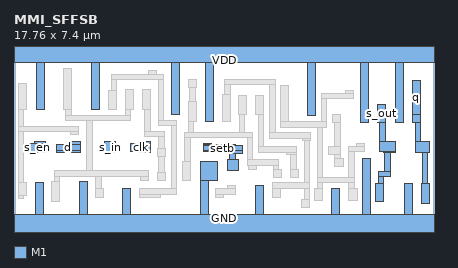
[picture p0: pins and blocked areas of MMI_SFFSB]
MACRO MMI_SFFSB
	CLASS CORE ;
	FOREIGN MMI_SFFSB 0 0 ;
	SIZE 17.76 BY 7.4 ;
	SYMMETRY X Y ;
	SITE CORE1 ;
	PIN d
		DIRECTION input ;
		USE SIGNAL ;
		PORT
			LAYER M1 ;
			RECT 1.79 3.435 2.13 3.465 ;
			LAYER M1 ;
			RECT 2.365 3.435 2.815 3.555 ;
			LAYER M1 ;
			RECT 1.79 3.205 2.815 3.435 ;
			LAYER M1 ;
			RECT 1.79 3.125 2.13 3.205 ;
			LAYER M1 ;
			RECT 2.365 3.105 2.815 3.205 ;
		END
		AntennaGateArea 0.4968 ;
	END d
	PIN GND
		DIRECTION inout ;
		USE GROUND ;
		PORT
			LAYER M1 ;
			RECT 7.905 1.905 8.6 2.745 ;
			LAYER M1 ;
			RECT 0.9 0.5 1.24 1.82 ;
			LAYER M1 ;
			RECT 2.75 0.5 3.09 1.87 ;
			LAYER M1 ;
			RECT 4.6 0.5 4.94 1.57 ;
			LAYER M1 ;
			RECT 7.905 0.5 8.245 1.905 ;
			LAYER M1 ;
			RECT 10.215 0.5 10.555 1.705 ;
			LAYER M1 ;
			RECT 13.445 0.5 13.785 1.6 ;
			LAYER M1 ;
			RECT 14.735 0.5 15.075 2.855 ;
			LAYER M1 ;
			RECT 16.495 0.5 16.835 1.8 ;
			LAYER M1 ;
			RECT 0 -0.5 17.76 0.5 ;
		END
	END GND
	PIN q
		DIRECTION output ;
		USE SIGNAL ;
		PORT
			LAYER M1 ;
			RECT 16.84 4.73 17.18 6.15 ;
			LAYER M1 ;
			RECT 16.84 4.39 17.19 4.73 ;
			LAYER M1 ;
			RECT 16.96 3.555 17.19 4.39 ;
			LAYER M1 ;
			RECT 16.96 3.11 17.56 3.555 ;
			LAYER M1 ;
			RECT 17.265 1.8 17.495 3.11 ;
			LAYER M1 ;
			RECT 17.215 0.96 17.555 1.8 ;
		END
		AntennaDiffArea 1.3248 ;
	END q
	PIN s_in
		DIRECTION input ;
		USE SIGNAL ;
		PORT
			LAYER M1 ;
			RECT 3.845 3.105 4.295 3.555 ;
		END
		AntennaGateArea 0.2484 ;
	END s_in
	PIN s_en
		DIRECTION input ;
		USE SIGNAL ;
		PORT
			LAYER M1 ;
			RECT 0.885 3.5 1.335 3.555 ;
			LAYER M1 ;
			RECT 0.66 3.16 1.335 3.5 ;
			LAYER M1 ;
			RECT 0.885 3.105 1.335 3.16 ;
		END
		AntennaGateArea 1.0404 ;
	END s_en
	PIN VDD
		DIRECTION inout ;
		USE POWER ;
		PORT
			LAYER M1 ;
			RECT 0 6.9 17.76 7.9 ;
			LAYER M1 ;
			RECT 0.94 4.91 1.28 6.9 ;
			LAYER M1 ;
			RECT 3.28 4.91 3.62 6.9 ;
			LAYER M1 ;
			RECT 6.65 4.705 6.99 6.9 ;
			LAYER M1 ;
			RECT 8.09 4.43 8.43 6.9 ;
			LAYER M1 ;
			RECT 12.42 4.66 12.76 6.9 ;
			LAYER M1 ;
			RECT 14.64 4.39 14.98 6.9 ;
			LAYER M1 ;
			RECT 16.12 4.39 16.46 6.9 ;
		END
	END VDD
	PIN s_out
		DIRECTION output ;
		USE SIGNAL ;
		PORT
			LAYER M1 ;
			RECT 15.36 4.39 15.7 5.15 ;
			LAYER M1 ;
			RECT 15.47 3.555 15.7 4.39 ;
			LAYER M1 ;
			RECT 15.47 3.17 16.135 3.555 ;
			LAYER M1 ;
			RECT 15.645 3.105 16.135 3.17 ;
			LAYER M1 ;
			RECT 15.685 2.305 15.915 3.105 ;
			LAYER M1 ;
			RECT 15.415 2.075 15.915 2.305 ;
			LAYER M1 ;
			RECT 15.415 1.8 15.645 2.075 ;
			LAYER M1 ;
			RECT 15.305 1.04 15.645 1.8 ;
		END
		AntennaDiffArea 0.8568 ;
	END s_out
	PIN setb
		DIRECTION input ;
		USE SIGNAL ;
		PORT
			LAYER M1 ;
			RECT 8.025 3.435 8.365 3.5 ;
			LAYER M1 ;
			RECT 8.025 3.385 9.355 3.435 ;
			LAYER M1 ;
			RECT 8.025 3.205 9.645 3.385 ;
			LAYER M1 ;
			RECT 8.025 3.16 8.365 3.205 ;
			LAYER M1 ;
			RECT 9.125 3.045 9.645 3.205 ;
			LAYER M1 ;
			RECT 9.125 2.815 9.355 3.045 ;
			LAYER M1 ;
			RECT 9.025 2.365 9.475 2.815 ;
		END
		AntennaGateArea 0.6552 ;
	END setb
	PIN clk
		DIRECTION input ;
		USE CLOCK ;
		PORT
			LAYER M1 ;
			RECT 5.325 3.495 5.775 3.555 ;
			LAYER M1 ;
			RECT 4.94 3.155 5.775 3.495 ;
			LAYER M1 ;
			RECT 5.325 3.105 5.775 3.155 ;
		END
		AntennaGateArea 0.6408 ;
	END clk
	OBS
		LAYER M1 ;
		RECT 0.18 4.91 0.52 6.03 ;
		LAYER M1 ;
		RECT 2.09 4.91 2.43 6.67 ;
		LAYER M1 ;
		RECT 5.7 6.405 6.04 6.555 ;
		LAYER M1 ;
		RECT 4.11 6.175 6.32 6.405 ;
		LAYER M1 ;
		RECT 4.11 5.75 4.34 6.175 ;
		LAYER M1 ;
		RECT 4 4.91 4.34 5.75 ;
		LAYER M1 ;
		RECT 4.7 4.93 5.04 5.77 ;
		LAYER M1 ;
		RECT 5.42 4.93 5.76 5.77 ;
		LAYER M1 ;
		RECT 0.18 4.22 0.41 4.91 ;
		LAYER M1 ;
		RECT 2.185 4.68 2.415 4.91 ;
		LAYER M1 ;
		RECT 4.7 4.68 4.93 4.93 ;
		LAYER M1 ;
		RECT 2.185 4.45 4.93 4.68 ;
		LAYER M1 ;
		RECT 0.18 3.99 2.71 4.22 ;
		LAYER M1 ;
		RECT 0.18 1.82 0.41 3.99 ;
		LAYER M1 ;
		RECT 2.37 3.88 2.71 3.99 ;
		LAYER M1 ;
		RECT 3.08 2.33 3.31 4.45 ;
		LAYER M1 ;
		RECT 5.53 4.015 5.76 4.93 ;
		LAYER M1 ;
		RECT 6.09 4.475 6.32 6.175 ;
		LAYER M1 ;
		RECT 7.38 5.85 7.72 6.19 ;
		LAYER M1 ;
		RECT 7.435 5.27 7.665 5.85 ;
		LAYER M1 ;
		RECT 6.09 4.245 6.88 4.475 ;
		LAYER M1 ;
		RECT 5.53 3.785 6.355 4.015 ;
		LAYER M1 ;
		RECT 6.125 3.265 6.355 3.785 ;
		LAYER M1 ;
		RECT 6.08 2.925 6.42 3.265 ;
		LAYER M1 ;
		RECT 1.71 2.1 5.7 2.33 ;
		LAYER M1 ;
		RECT 6.125 2.27 6.355 2.925 ;
		LAYER M1 ;
		RECT 1.71 1.87 1.94 2.1 ;
		LAYER M1 ;
		RECT 0.18 1.3 0.52 1.82 ;
		LAYER M1 ;
		RECT 0.18 1.18 0.41 1.3 ;
		LAYER M1 ;
		RECT 1.6 1.03 1.94 1.87 ;
		LAYER M1 ;
		RECT 3.45 1.57 3.68 2.1 ;
		LAYER M1 ;
		RECT 5.36 1.93 5.7 2.1 ;
		LAYER M1 ;
		RECT 6.08 1.93 6.42 2.27 ;
		LAYER M1 ;
		RECT 6.65 1.57 6.88 4.245 ;
		LAYER M1 ;
		RECT 7.37 4.43 7.71 5.27 ;
		LAYER M1 ;
		RECT 8.92 5.98 11.04 6.21 ;
		LAYER M1 ;
		RECT 8.92 5.55 9.15 5.98 ;
		LAYER M1 ;
		RECT 8.81 4.43 9.15 5.55 ;
		LAYER M1 ;
		RECT 9.51 4.695 9.85 5.535 ;
		LAYER M1 ;
		RECT 10.23 4.695 10.57 5.535 ;
		LAYER M1 ;
		RECT 7.37 3.965 7.6 4.43 ;
		LAYER M1 ;
		RECT 9.515 3.965 9.745 4.695 ;
		LAYER M1 ;
		RECT 7.22 3.735 10.105 3.965 ;
		LAYER M1 ;
		RECT 7.22 2.745 7.45 3.735 ;
		LAYER M1 ;
		RECT 7.11 1.905 7.45 2.745 ;
		LAYER M1 ;
		RECT 9.875 2.805 10.105 3.735 ;
		LAYER M1 ;
		RECT 10.34 3.355 10.57 4.695 ;
		LAYER M1 ;
		RECT 10.81 3.95 11.04 5.98 ;
		LAYER M1 ;
		RECT 11.27 4.41 11.61 5.935 ;
		LAYER M1 ;
		RECT 14.03 5.61 14.37 5.72 ;
		LAYER M1 ;
		RECT 12.99 5.38 14.37 5.61 ;
		LAYER M1 ;
		RECT 12.99 4.41 13.22 5.38 ;
		LAYER M1 ;
		RECT 11.27 4.185 13.22 4.41 ;
		LAYER M1 ;
		RECT 13.45 4.39 13.79 4.73 ;
		LAYER M1 ;
		RECT 11.38 4.18 13.22 4.185 ;
		LAYER M1 ;
		RECT 10.81 3.72 12.52 3.95 ;
		LAYER M1 ;
		RECT 12.18 3.61 12.52 3.72 ;
		LAYER M1 ;
		RECT 10.34 3.125 11.925 3.355 ;
		LAYER M1 ;
		RECT 11.51 3.015 11.925 3.125 ;
		LAYER M1 ;
		RECT 9.875 2.575 11.205 2.805 ;
		LAYER M1 ;
		RECT 9.935 2.37 10.275 2.575 ;
		LAYER M1 ;
		RECT 10.975 2.405 11.205 2.575 ;
		LAYER M1 ;
		RECT 11.695 2.405 11.925 3.015 ;
		LAYER M1 ;
		RECT 10.975 2.065 11.315 2.405 ;
		LAYER M1 ;
		RECT 11.695 2.065 12.035 2.405 ;
		LAYER M1 ;
		RECT 3.45 1.19 3.79 1.57 ;
		LAYER M1 ;
		RECT 5.32 1.34 6.88 1.57 ;
		LAYER M1 ;
		RECT 5.32 1.19 6.18 1.34 ;
		LAYER M1 ;
		RECT 12.265 1.835 12.495 3.61 ;
		LAYER M1 ;
		RECT 9.025 1.565 9.365 1.705 ;
		LAYER M1 ;
		RECT 8.505 1.335 9.365 1.565 ;
		LAYER M1 ;
		RECT 8.505 1.225 8.845 1.335 ;
		LAYER M1 ;
		RECT 10.935 1.605 12.495 1.835 ;
		LAYER M1 ;
		RECT 10.935 1.185 11.275 1.605 ;
		LAYER M1 ;
		RECT 12.265 1.12 12.495 1.605 ;
		LAYER M1 ;
		RECT 12.835 2.06 13.065 4.18 ;
		LAYER M1 ;
		RECT 13.56 3.375 13.79 4.39 ;
		LAYER M1 ;
		RECT 13.295 3.035 13.79 3.375 ;
		LAYER M1 ;
		RECT 14.495 3.365 14.835 3.475 ;
		LAYER M1 ;
		RECT 13.56 2.855 13.79 3.035 ;
		LAYER M1 ;
		RECT 14.165 3.135 14.835 3.365 ;
		LAYER M1 ;
		RECT 13.56 2.515 13.925 2.855 ;
		LAYER M1 ;
		RECT 14.165 2.06 14.395 3.135 ;
		LAYER M1 ;
		RECT 12.835 1.83 14.395 2.06 ;
		LAYER M1 ;
		RECT 12.835 1.6 13.065 1.83 ;
		LAYER M1 ;
		RECT 14.165 1.6 14.395 1.83 ;
		LAYER M1 ;
		RECT 12.155 0.78 12.495 1.12 ;
		LAYER M1 ;
		RECT 12.725 1.06 13.065 1.6 ;
		LAYER M1 ;
		RECT 14.165 1.06 14.505 1.6 ;
	END
END MMI_SFFSB
